VERSION 5.7 ;
  NOWIREEXTENSIONATPIN ON ;
  DIVIDERCHAR "/" ;
  BUSBITCHARS "[]" ;
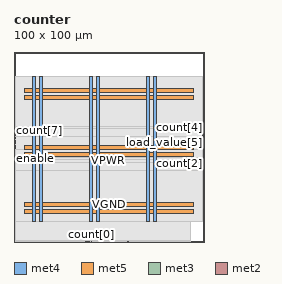
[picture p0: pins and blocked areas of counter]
MACRO counter
  CLASS BLOCK ;
  FOREIGN counter ;
  ORIGIN 0.000 0.000 ;
  SIZE 100.000 BY 100.000 ;
  PIN VGND
    DIRECTION INOUT ;
    USE GROUND ;
    PORT
      LAYER met4 ;
        RECT 13.220 10.640 15.220 87.280 ;
    END
    PORT
      LAYER met4 ;
        RECT 43.220 10.640 45.220 87.280 ;
    END
    PORT
      LAYER met4 ;
        RECT 73.220 10.640 75.220 87.280 ;
    END
    PORT
      LAYER met5 ;
        RECT 5.520 18.580 94.300 20.580 ;
    END
    PORT
      LAYER met5 ;
        RECT 5.520 48.580 94.300 50.580 ;
    END
    PORT
      LAYER met5 ;
        RECT 5.520 78.580 94.300 80.580 ;
    END
  END VGND
  PIN VPWR
    DIRECTION INOUT ;
    USE POWER ;
    PORT
      LAYER met4 ;
        RECT 9.520 10.640 11.520 87.280 ;
    END
    PORT
      LAYER met4 ;
        RECT 39.520 10.640 41.520 87.280 ;
    END
    PORT
      LAYER met4 ;
        RECT 69.520 10.640 71.520 87.280 ;
    END
    PORT
      LAYER met5 ;
        RECT 5.520 14.880 94.300 16.880 ;
    END
    PORT
      LAYER met5 ;
        RECT 5.520 44.880 94.300 46.880 ;
    END
    PORT
      LAYER met5 ;
        RECT 5.520 74.880 94.300 76.880 ;
    END
  END VPWR
  PIN clk
    DIRECTION INPUT ;
    USE SIGNAL ;
    ANTENNAGATEAREA 0.852000 ;
    PORT
      LAYER met3 ;
        RECT 0.000 53.080 0.600 53.680 ;
    END
  END clk
  PIN count[0]
    DIRECTION OUTPUT ;
    USE SIGNAL ;
    ANTENNADIFFAREA 0.702900 ;
    PORT
      LAYER met2 ;
        RECT 40.570 0.000 40.850 0.280 ;
    END
  END count[0]
  PIN count[1]
    DIRECTION OUTPUT ;
    USE SIGNAL ;
    ANTENNADIFFAREA 0.702900 ;
    PORT
      LAYER met2 ;
        RECT 37.810 0.000 38.090 0.280 ;
    END
  END count[1]
  PIN count[2]
    DIRECTION OUTPUT ;
    USE SIGNAL ;
    ANTENNADIFFAREA 0.702900 ;
    PORT
      LAYER met3 ;
        RECT 99.400 40.840 100.000 41.440 ;
    END
  END count[2]
  PIN count[3]
    DIRECTION OUTPUT ;
    USE SIGNAL ;
    ANTENNADIFFAREA 0.702900 ;
    PORT
      LAYER met3 ;
        RECT 99.400 38.120 100.000 38.720 ;
    END
  END count[3]
  PIN count[4]
    DIRECTION OUTPUT ;
    USE SIGNAL ;
    ANTENNADIFFAREA 0.702900 ;
    PORT
      LAYER met3 ;
        RECT 99.400 59.880 100.000 60.480 ;
    END
  END count[4]
  PIN count[5]
    DIRECTION OUTPUT ;
    USE SIGNAL ;
    ANTENNADIFFAREA 0.702900 ;
    PORT
      LAYER met3 ;
        RECT 99.400 58.520 100.000 59.120 ;
    END
  END count[5]
  PIN count[6]
    DIRECTION OUTPUT ;
    USE SIGNAL ;
    ANTENNADIFFAREA 0.702900 ;
    PORT
      LAYER met3 ;
        RECT 0.000 57.160 0.600 57.760 ;
    END
  END count[6]
  PIN count[7]
    DIRECTION OUTPUT ;
    USE SIGNAL ;
    ANTENNADIFFAREA 0.702900 ;
    PORT
      LAYER met3 ;
        RECT 0.000 58.520 0.600 59.120 ;
    END
  END count[7]
  PIN enable
    DIRECTION INPUT ;
    USE SIGNAL ;
    ANTENNAGATEAREA 0.213000 ;
    PORT
      LAYER met3 ;
        RECT 0.000 43.560 0.600 44.160 ;
    END
  END enable
  PIN load
    DIRECTION INPUT ;
    USE SIGNAL ;
    ANTENNAGATEAREA 0.213000 ;
    PORT
      LAYER met3 ;
        RECT 0.000 49.000 0.600 49.600 ;
    END
  END load
  PIN load_value[0]
    DIRECTION INPUT ;
    USE SIGNAL ;
    ANTENNAGATEAREA 0.213000 ;
    PORT
      LAYER met2 ;
        RECT 39.650 0.000 39.930 0.280 ;
    END
  END load_value[0]
  PIN load_value[1]
    DIRECTION INPUT ;
    USE SIGNAL ;
    ANTENNAGATEAREA 0.213000 ;
    PORT
      LAYER met2 ;
        RECT 38.730 0.000 39.010 0.280 ;
    END
  END load_value[1]
  PIN load_value[2]
    DIRECTION INPUT ;
    USE SIGNAL ;
    ANTENNAGATEAREA 0.213000 ;
    PORT
      LAYER met3 ;
        RECT 99.400 39.480 100.000 40.080 ;
    END
  END load_value[2]
  PIN load_value[3]
    DIRECTION INPUT ;
    USE SIGNAL ;
    ANTENNAGATEAREA 0.213000 ;
    PORT
      LAYER met2 ;
        RECT 59.890 0.000 60.170 0.280 ;
    END
  END load_value[3]
  PIN load_value[4]
    DIRECTION INPUT ;
    USE SIGNAL ;
    ANTENNAGATEAREA 0.213000 ;
    PORT
      LAYER met3 ;
        RECT 99.400 57.160 100.000 57.760 ;
    END
  END load_value[4]
  PIN load_value[5]
    DIRECTION INPUT ;
    USE SIGNAL ;
    ANTENNAGATEAREA 0.213000 ;
    PORT
      LAYER met3 ;
        RECT 99.400 55.800 100.000 56.400 ;
    END
  END load_value[5]
  PIN load_value[6]
    DIRECTION INPUT ;
    USE SIGNAL ;
    ANTENNAGATEAREA 0.213000 ;
    PORT
      LAYER met3 ;
        RECT 0.000 54.440 0.600 55.040 ;
    END
  END load_value[6]
  PIN load_value[7]
    DIRECTION INPUT ;
    USE SIGNAL ;
    ANTENNAGATEAREA 0.213000 ;
    PORT
      LAYER met3 ;
        RECT 0.000 55.800 0.600 56.400 ;
    END
  END load_value[7]
  PIN rst_n
    DIRECTION INPUT ;
    USE SIGNAL ;
    ANTENNAGATEAREA 0.213000 ;
    PORT
      LAYER met3 ;
        RECT 0.000 50.360 0.600 50.960 ;
    END
  END rst_n
  PIN up
    DIRECTION INPUT ;
    USE SIGNAL ;
    ANTENNAGATEAREA 0.213000 ;
    PORT
      LAYER met3 ;
        RECT 0.000 51.720 0.600 52.320 ;
    END
  END up
  OBS
      LAYER nwell ;
        RECT 5.330 10.795 94.490 87.125 ;
      LAYER li1 ;
        RECT 5.520 10.795 94.300 87.125 ;
      LAYER met1 ;
        RECT 0.990 10.640 94.300 87.280 ;
      LAYER met2 ;
        RECT 1.010 0.560 92.830 87.225 ;
        RECT 1.010 0.280 37.530 0.560 ;
        RECT 38.370 0.280 38.450 0.560 ;
        RECT 39.290 0.280 39.370 0.560 ;
        RECT 40.210 0.280 40.290 0.560 ;
        RECT 41.130 0.280 59.610 0.560 ;
        RECT 60.450 0.280 92.830 0.560 ;
      LAYER met3 ;
        RECT 0.600 60.880 99.400 87.205 ;
        RECT 0.600 59.520 99.000 60.880 ;
        RECT 1.000 55.400 99.000 59.520 ;
        RECT 1.000 48.600 99.400 55.400 ;
        RECT 0.600 44.560 99.400 48.600 ;
        RECT 1.000 43.160 99.400 44.560 ;
        RECT 0.600 41.840 99.400 43.160 ;
        RECT 0.600 37.720 99.000 41.840 ;
        RECT 0.600 10.715 99.400 37.720 ;
  END
END counter
END LIBRARY

